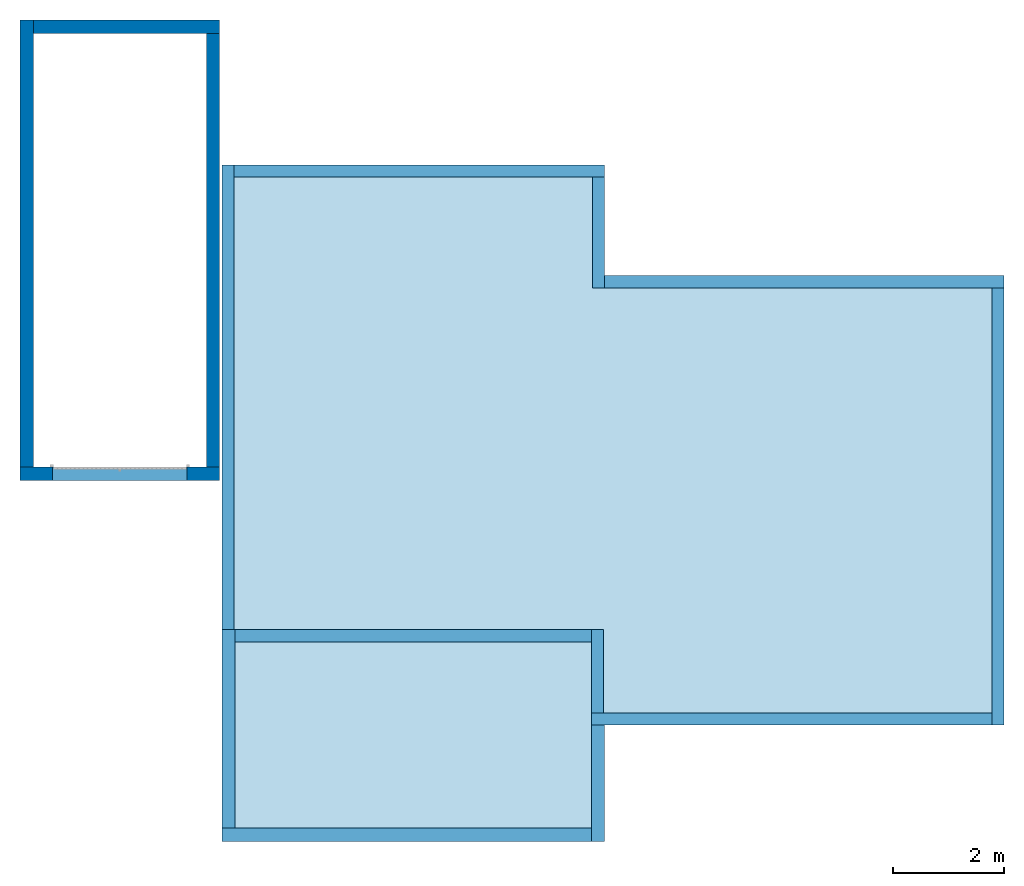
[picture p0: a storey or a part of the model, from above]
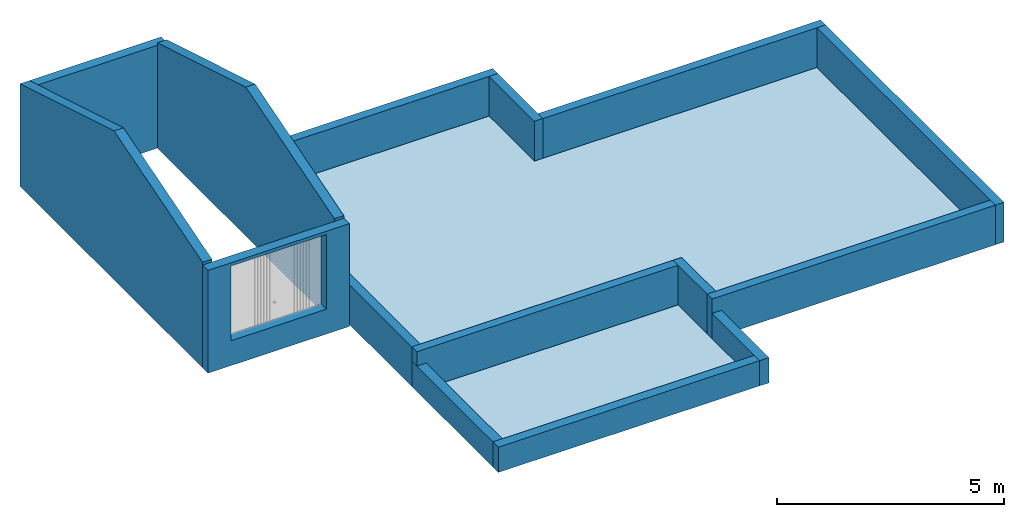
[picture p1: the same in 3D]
Properties of the parts of a building model (IFC2X3)

# File
Description: ViewDefinition [CoordinationView_V2.0]
File name: 0001
Time: 2021-03-25T11:47:55
Written by: The EXPRESS Data Manager Version 5.02.0100.07 : 28 Aug 2013
Made in: 21.0.0.383 - Exporter 21.0.0.383 - Interface utilisateur alternative 21.0.0.383
Comment: STEP Physical File produced by: The EXPRESS Data Manager Version 5.02.0100.07 : 28 Aug 2013 * Module: EDMstepFileFactory/EDMstandAlone * Creation date: Thu Mar 25 11:47:55 2021 * Host: db501 * Database: C:\Users\scosse1\AppData\Local\Temp\aa0bf1f8-5ca8-4587-8f95-3775c004460e\7c48a7ac-f314-43d9-8564-91e496e13a8a\ifc * Database version: 5507 * Database creation date: Thu Mar 25 11:47:32 2021 * Schema: IFC2X3 * Model: DataRepository.ifc * Model creation date: Thu Mar 25 11:47:32 2021 * Header model: DataRepository.ifc_HeaderModel * Header model creation date: Thu Mar 25 11:47:32 2021 * EDMuser: sdai-user * EDMgroup: sdai-group * License ID and type: 5605 : Permanent license. Expiry date: * EDMstepFileFactory options: 020000

# IfcProject, 0001
LongName: Nom du projet; Phase: Etat du projet

# IfcSite, Surface:318536
RefLatitude: 48, 52, 0, 117187; RefLongitude: 2, 19, 59, 880409; RefElevation: 0 m

# IfcBuilding
Pset_BuildingCommon - NumberOfStoreys: 6

# IfcBuildingStorey: Niveau:Ligne du Niveau (6)
Name | LongName | Elevation (m)
TN | TN | -1.07
GARAGE | GARAGE | -0.47
TERRASSE | TERRASSE | -0.17
RDC | RDC | -1.94916e-14
ARARSE GARAGE | ARARSE GARAGE | 1.7
ARASE 1 | ARASE 1 | 2.75

# IfcSpace: Cuisine 8:317210, 8
In: RDC
LongName: Cuisine; InteriorOrExteriorSpace: INTERNAL
Pset_SpaceCommon - Reference: Cuisine 8

# IfcSpace: Pièce 5:317039, 5
In: RDC
LongName: Pièce; InteriorOrExteriorSpace: INTERNAL
Pset_SpaceCommon - Reference: Pièce 5

# IfcSpace: SDB 1:317027, 1
In: RDC
LongName: SDB; InteriorOrExteriorSpace: INTERNAL
Pset_SpaceCommon - Reference: SDB 1

# IfcSpace: Salon Séjour 6:317042, 6
In: RDC
LongName: Salon Séjour; InteriorOrExteriorSpace: INTERNAL
Pset_SpaceCommon - Reference: Salon Séjour 6

# IfcSpace: WC 7:317045, 7
In: RDC
LongName: WC; InteriorOrExteriorSpace: INTERNAL
Pset_SpaceCommon - Reference: WC 7

# IfcSpace: chambre 1 4:317036, 4
In: RDC
LongName: chambre 1; InteriorOrExteriorSpace: INTERNAL
Pset_SpaceCommon - Reference: chambre 1 4

# IfcSpace: chambre 2 3:317033, 3
In: RDC
LongName: chambre 2; InteriorOrExteriorSpace: INTERNAL
Pset_SpaceCommon - Reference: chambre 2 3

# IfcSpace: chambre 3 2:317030, 2
In: RDC
LongName: chambre 3; InteriorOrExteriorSpace: INTERNAL
Pset_SpaceCommon - Reference: chambre 3 2

# IfcBuildingElementProxy: Arbre 3D - Hêtre:Hêtre - 4 m, Arbre 3D - Hêtre:Hêtre - 4 m:319941
In: RDC
Type - Pset_BuildingElementProxyCommon - Reference: Hêtre - 4 m
Type - Pset_QuantityTakeOff - Reference: Hêtre - 4 m
Pset_BuildingElementProxyCommon - sets with these values: 2

# IfcBuildingElementProxy: Plaque vitrocéramique - 4 foyers:600mm x 600mm, Plaque vitrocéramique - 4 foyers:600mm x 600mm:305606
In: 8
Type - Material: Métal - Chrome, Peinture - Grise, Verre - Plaque vitrocéramique
Type - Pset_BuildingElementProxyCommon - Reference: 600mm x 600mm
Type - Pset_QuantityTakeOff - Reference: 600mm x 600mm
Material: Métal - Chrome, Verre - Plaque vitrocéramique
Pset_BuildingElementProxyCommon - sets with these values: 2

# IfcBuildingElementProxy: RPC Arbre - Tropical:Palmier princesse - 3.6 mètres, RPC Arbre - Tropical:Palmier princesse - 3.6 mètres:323484
In: RDC
Type - Pset_BuildingElementProxyCommon - Reference: Palmier princesse - 3.6 mètres
Type - Pset_QuantityTakeOff - Reference: Palmier princesse - 3.6 mètres
Pset_BuildingElementProxyCommon - sets with these values: 2

# IfcBuildingElementProxy: RPC Femme:Lisa, RPC Femme:Lisa:324221
In: RDC
Type - Pset_BuildingElementProxyCommon - Reference: Lisa
Type - Pset_QuantityTakeOff - Reference: Lisa
Pset_BuildingElementProxyCommon - sets with these values: 2

# IfcCovering: Plafond composé:Plafond avec isolation 20 cm, Plafond composé:Plafond avec isolation 20 cm:278956
In: RDC
Type - PredefinedType: CEILING
Type - Pset_CoveringCommon - Reference: Plafond avec isolation 20 cm; TotalThickness: 0.22 m
Type - Pset_QuantityTakeOff - Reference: Plafond avec isolation 20 cm
Material: Maçonnerie - Isolant 0.2 m, Faux-plafond - Trame 600 x 600 0.02 m

# IfcDoor: Ext. Simple:Lisse - 0.90 m x 2.15 m, Ext. Simple:Lisse - 0.90 m x 2.15 m:270962
In: RDC
Type - OperationType: SINGLE_SWING_LEFT; ParameterTakesPrecedence: no; Sizeable: no; Material: PVC - Blanc (3)
Type - Ext. Simple:Lisse - 0.90 m x 2.15 m:270962 - PanelOperation: SWINGING
Type - Pset_DoorCommon - IsExternal: no; Reference: Lisse - 0.90 m x 2.15 m; ThermalTransmittance: 5.5617 kg/K/s3
Type - Pset_QuantityTakeOff - Reference: Lisse - 0.90 m x 2.15 m
OverallHeight: 2.2 m; OverallWidth: 1 m; Material: PVC - Blanc
Pset_DoorCommon - IsExternal: yes

# IfcDoor: Garage basculante:2.4m x 2m, Garage basculante:2.4m x 2m:297785
In: RDC
Type - OperationType: ROLLINGUP; ParameterTakesPrecedence: no; Sizeable: no; Material: Plastique - Noir, Peinture - Grise (2)
Type - Garage basculante:2.4m x 2m:297785 - PanelOperation: ROLLINGUP
Type - Pset_DoorCommon - IsExternal: no; Reference: 2.4m x 2m; ThermalTransmittance: 3.7021 kg/K/s3
Type - Pset_QuantityTakeOff - Reference: 2.4m x 2m
OverallHeight: 2.43 m; OverallWidth: 2.015 m; Material: Plastique - Noir, Peinture - Grise
Pset_DoorCommon - IsExternal: yes

# IfcDoor: Int. Simple:PP (0.73m x 2.04m), Int. Simple:PP (0.73m x 2.04m):277916
In: RDC
Type - ParameterTakesPrecedence: no; Sizeable: no; Material: Finition Peinture - Blanc satiné, Bois - Cadre de porte (2), Bois - Panneau de porte
Type - Pset_DoorCommon - IsExternal: no; Reference: PP (0.73m x 2.04m); ThermalTransmittance: 3.7021 kg/K/s3
Type - Pset_QuantityTakeOff - Reference: PP (0.73m x 2.04m)
OverallHeight: 2.075 m; OverallWidth: 0.8 m; Material: Finition Peinture - Blanc satiné, Bois - Panneau de porte, Bois - Cadre de porte

# IfcDoor: Int. Simple:PP (0.83m x 2.04m), Int. Simple:PP (0.83m x 2.04m):277793
In: RDC
Type - ParameterTakesPrecedence: no; Sizeable: no; Material: Bois - Cadre de porte (2), Finition Peinture - Blanc satiné, Bois - Panneau de porte
Type - Pset_DoorCommon - IsExternal: no; Reference: PP (0.83m x 2.04m); ThermalTransmittance: 3.7021 kg/K/s3
Type - Pset_QuantityTakeOff - Reference: PP (0.83m x 2.04m)
OverallHeight: 2.075 m; OverallWidth: 0.9 m; Material: Finition Peinture - Blanc satiné, Bois - Panneau de porte, Bois - Cadre de porte

# IfcDoor: Int. Simple:PP (0.83m x 2.04m) (4)
In: RDC
Type - ParameterTakesPrecedence: no; Sizeable: no; Material: Bois - Panneau de porte, Bois - Cadre de porte (2), Finition Peinture - Blanc satiné
Type - Pset_DoorCommon - IsExternal: no; Reference: PP (0.83m x 2.04m); ThermalTransmittance: 3.7021 kg/K/s3
Type - Pset_QuantityTakeOff - Reference: PP (0.83m x 2.04m)
OverallHeight: 2.075 m; OverallWidth: 0.9 m; Material: Finition Peinture - Blanc satiné, Bois - Panneau de porte, Bois - Cadre de porte
Name (Int. Simple:PP (0.83m x 2.04m):...)
277585
277677
277709
277755

# IfcDoor: Int. Simple:PP (0.83m x 2.04m), Int. Simple:PP (0.83m x 2.04m):277627
In: RDC
Type - ParameterTakesPrecedence: no; Sizeable: no; Material: Bois - Panneau de porte, Finition Peinture - Blanc satiné, Bois - Cadre de porte (2)
Type - Pset_DoorCommon - IsExternal: no; Reference: PP (0.83m x 2.04m); ThermalTransmittance: 3.7021 kg/K/s3
Type - Pset_QuantityTakeOff - Reference: PP (0.83m x 2.04m)
OverallHeight: 2.075 m; OverallWidth: 0.9 m; Material: Finition Peinture - Blanc satiné, Bois - Panneau de porte, Bois - Cadre de porte

# IfcDoor: Panneau Plein - Ouverture ext:0.73m x 2.10m, Panneau Plein - Ouverture ext:0.73m x 2.10m:272892
In: RDC
Type - OperationType: SINGLE_SWING_RIGHT; ParameterTakesPrecedence: no; Sizeable: no; Material: PVC - Blanc (3)
Type - Panneau Plein - Ouverture ext:0.73m x 2.10m:272892 - PanelOperation: SWINGING
Type - Pset_DoorCommon - IsExternal: no; Reference: 0.73m x 2.10m; ThermalTransmittance: 5.5617 kg/K/s3
Type - Pset_QuantityTakeOff - Reference: 0.73m x 2.10m
OverallHeight: 2.15 m; OverallWidth: 0.83 m; Material: PVC - Blanc

# IfcFlowTerminal: Chauffe eau:Chauffe eau, Chauffe eau:Chauffe eau:315632
In: RDC
Type - Pset_QuantityTakeOff - Reference: Chauffe eau
Pset_DistributionFlowElementCommon - Reference: Chauffe eau; sets with these values: 3

# IfcFlowTerminal: Grand évier - 2 bacs:1160mm x 500mm, Grand évier - 2 bacs:1160mm x 500mm:302428
In: 8
Type - Material: Plastique - Ton pierre, Plastique - Blanc brillant
Type - Pset_QuantityTakeOff - Reference: 1160mm x 500mm
Material: Plastique - Blanc brillant, Plastique - Ton pierre
Pset_DistributionFlowElementCommon - Reference: 1160mm x 500mm; sets with these values: 2

# IfcFlowTerminal: Lavabo moderne:Lavabo moderne, Lavabo moderne:Lavabo moderne:307324
In: 1
Type - Material: Métal - Chrome poli, Bois - Noyer naturel, Porcelaine - Blanche
Type - Pset_QuantityTakeOff - Reference: Lavabo moderne
Material: Métal - Chrome poli, Porcelaine - Blanche, Bois - Noyer naturel
Pset_DistributionFlowElementCommon - Reference: Lavabo moderne; sets with these values: 3

# IfcFlowTerminal: WC à réservoir:WC à réservoir, WC à réservoir:WC à réservoir:309013
In: 7
Type - Material: Porcelaine - Blanche, Métal - Chrome
Type - Pset_QuantityTakeOff - Reference: WC à réservoir
Pset_DistributionFlowElementCommon - Reference: WC à réservoir; sets with these values: 3

# IfcFurnishingElement: Canapé 3 places - 01:Canapé 3 places - 01, Canapé 3 places - 01:Canapé 3 places - 01:311175
In: 6
Type - Material: Métal - Chrome, Tissu - Fuschia
Type - Pset_QuantityTakeOff - Reference: Canapé 3 places - 01
Material: Tissu - Fuschia, Métal - Chrome

# IfcFurnishingElement: Lit double - 01:1346mm x 1880mm (3)
Type - Material: Bois - Bouleau, Textile - Blanc
Type - Pset_QuantityTakeOff - Reference: 1346mm x 1880mm
Name (Lit double - 01:1346mm x 1880mm:...) | In
309758 | 2
309913 | 4
309986 | 3

# IfcFurnishingElement: Table basse:900mm x 900mm x 350mm, Table basse:900mm x 900mm x 350mm:312634
In: 6
Type - Material: Métal - Alu brossé, Bois - Exotique
Type - Pset_QuantityTakeOff - Reference: 900mm x 900mm x 350mm
Material: Bois - Exotique, Métal - Alu brossé

# IfcFurnishingElement: Table et chaises:1100mm x 1100mm x 760mm, Table et chaises:1100mm x 1100mm x 760mm:314958
In: 6
Type - Material: Bois - Exotique (2), Verre - Opaque Blanc, Textile - Beige
Type - Pset_QuantityTakeOff - Reference: 1100mm x 1100mm x 760mm
Material: Bois - Exotique, Textile - Beige, Verre - Opaque Blanc

# IfcRoof: Toit de base:Toit - 200 mm (2)
Pset_QuantityTakeOff - Reference: Toit - 200 mm
Pset_RoofCommon - IsExternal: yes; Reference: Toit - 200 mm
Name (Toit de base:Toit - 200 mm:...) | In | ProjectedArea (m2) | TotalArea (m2)
287388 | ARASE 1 | 132.45 | 138.282
297901 | ARARSE GARAGE | 34.71 | 36.2383

# IfcSlab: Sol:Dalle en béton - 250 mm, Sol:Dalle en béton - 250 mm:298360
In: GARAGE
Type - PredefinedType: FLOOR; Material: Maçonnerie - Béton 0.25 m
Type - Pset_QuantityTakeOff - Reference: Dalle en béton - 250 mm
Type - Pset_ReinforcementBarPitchOfSlab - Reference: Dalle en béton - 250 mm
Type - Pset_SlabCommon - IsExternal: no; Reference: Dalle en béton - 250 mm
Pset_QuantityTakeOff - sets with these values: 2
Pset_SlabCommon - LoadBearing: no; PitchAngle: 0 deg

# IfcSlab: Sol:dalle béton 20 cm + 2 cm carrellage, Sol:dalle béton 20 cm + 2 cm carrellage:289247
In: TERRASSE
Type - PredefinedType: FLOOR; Material: Surface de dalle analytique 0.02 m, Maçonnerie - Béton 0.2 m
Type - Pset_QuantityTakeOff - Reference: dalle béton 20 cm + 2 cm carrellage
Type - Pset_ReinforcementBarPitchOfSlab - Reference: dalle béton 20 cm + 2 cm carrellage
Type - Pset_SlabCommon - IsExternal: no; Reference: dalle béton 20 cm + 2 cm carrellage
Pset_QuantityTakeOff - sets with these values: 2
Pset_SlabCommon - LoadBearing: no; PitchAngle: 0 deg

# IfcSlab: Sol:dalle béton 20 cm + 7 cm carrellage, Sol:dalle béton 20 cm + 7 cm carrellage:273148
In: RDC
Type - PredefinedType: FLOOR; Material: carrelage 0.07 m, Maçonnerie - Béton 0.2 m
Type - Pset_QuantityTakeOff - Reference: dalle béton 20 cm + 7 cm carrellage
Type - Pset_ReinforcementBarPitchOfSlab - Reference: dalle béton 20 cm + 7 cm carrellage
Type - Pset_SlabCommon - IsExternal: no; Reference: dalle béton 20 cm + 7 cm carrellage
Pset_QuantityTakeOff - sets with these values: 2
Pset_SlabCommon - LoadBearing: no; PitchAngle: 0 deg

# IfcSlab: Terre-plein:Terre-plein vs, Terre-plein:Terre-plein vs:324258
In: TN
Type - PredefinedType: FLOOR; Material: Herbe 0.01 m
Type - Pset_QuantityTakeOff - Reference: Terre-plein vs
Type - Pset_ReinforcementBarPitchOfSlab - Reference: Terre-plein vs
Type - Pset_SlabCommon - IsExternal: no; Reference: Terre-plein vs
Pset_QuantityTakeOff - sets with these values: 2
Pset_SlabCommon - PitchAngle: 0 deg

# IfcSlab: Toit de base:Toit - 200 mm (5)
Type - PredefinedType: ROOF
Type - Pset_QuantityTakeOff - Reference: Toit - 200 mm
Type - Pset_ReinforcementBarPitchOfSlab - Reference: Toit - 200 mm
Type - Pset_SlabCommon - IsExternal: yes; Reference: Toit - 200 mm
Material: Toit par défaut; Toit par défaut 0.2 m
Pset_QuantityTakeOff - sets with these values: 2
Pset_SlabCommon - PitchAngle: 16.6992 deg
Name (Toit de base:Toit - 200 mm:...) | In
3 x 287388 | ARASE 1
2 x 297901 | ARARSE GARAGE

# IfcWall: Mur de base:Int. Plâtre 70 mm, Mur de base:Int. Plâtre 70 mm:274840
In: RDC
Type - PredefinedType: STANDARD; Material: Mur par défaut 0.07 m
Type - Pset_QuantityTakeOff - Reference: Int. Plâtre 70 mm
Type - Pset_ReinforcementBarPitchOfWall - Reference: Int. Plâtre 70 mm
Type - Pset_WallCommon - IsExternal: no; Reference: Int. Plâtre 70 mm
Pset_QuantityTakeOff - sets with these values: 2
Pset_WallCommon - LoadBearing: no; ExtendToStructure: no

# IfcWallStandardCase: Mur de base:Ext. Parpaing 20 + Isolant 10 (8)
In: RDC
Type - PredefinedType: STANDARD; Material: Maçonnerie - Enduit 0.02 m, Blocs béton manufacturés 0.2 m, Maçonnerie - Isolant 0.1 m
Type - Pset_QuantityTakeOff - Reference: Ext. Parpaing 20 + Isolant 10
Type - Pset_ReinforcementBarPitchOfWall - Reference: Ext. Parpaing 20 + Isolant 10
Type - Pset_WallCommon - Reference: Ext. Parpaing 20 + Isolant 10; ThermalTransmittance: 6.5 kg/K/s3; IsExternal: no
Pset_QuantityTakeOff - sets with these values: 2
Pset_WallCommon - IsExternal: yes; ExtendToStructure: yes; LoadBearing: no
Name (Mur de base:Ext. Parpaing 20 + Isolant 10:...)
244761
244782
244849
244895
244950
244986
245107
245187

# IfcWallStandardCase: Mur de base:Int. Plâtre 70 mm (10)
In: RDC
Type - PredefinedType: STANDARD; Material: Mur par défaut 0.07 m
Type - Pset_QuantityTakeOff - Reference: Int. Plâtre 70 mm
Type - Pset_ReinforcementBarPitchOfWall - Reference: Int. Plâtre 70 mm
Type - Pset_WallCommon - IsExternal: no; Reference: Int. Plâtre 70 mm
Pset_QuantityTakeOff - sets with these values: 2
Pset_WallCommon - LoadBearing: no; ExtendToStructure: no
Name (Mur de base:Int. Plâtre 70 mm:...)
274764
275567
275614
275788
276101
276391
276780
277050
277229
277277

# IfcWallStandardCase: Mur de base:parpaing 20 + enduit 1 face 2 cm (8)
In: TN
Type - PredefinedType: STANDARD; Material: Maçonnerie - Enduit 0.02 m, Maçonnerie - Béton 0.2 m
Type - Pset_QuantityTakeOff - Reference: parpaing 20 + enduit 1 face 2 cm
Type - Pset_ReinforcementBarPitchOfWall - Reference: parpaing 20 + enduit 1 face 2 cm
Type - Pset_WallCommon - IsExternal: no; Reference: parpaing 20 + enduit 1 face 2 cm
Pset_QuantityTakeOff - sets with these values: 2
Pset_WallCommon - IsExternal: yes; LoadBearing: no; ExtendToStructure: no
Name (Mur de base:parpaing 20 + enduit 1 face 2 cm:...)
291139
291246
291309
291393
291573
291633
291901
292034

# IfcWallStandardCase: Mur de base:parpaing 20 + enduit 2 faces 2 cm (8)
Type - PredefinedType: STANDARD; Material: Maçonnerie - Enduit 0.02 m, Blocs béton manufacturés 0.2 m, Maçonnerie - Enduit 0.02 m
Type - Pset_QuantityTakeOff - Reference: parpaing 20 + enduit 2 faces 2 cm
Type - Pset_ReinforcementBarPitchOfWall - Reference: parpaing 20 + enduit 2 faces 2 cm
Type - Pset_WallCommon - IsExternal: no; Reference: parpaing 20 + enduit 2 faces 2 cm; ThermalTransmittance: 6.5 kg/K/s3
Pset_QuantityTakeOff - sets with these values: 2
Pset_WallCommon - IsExternal: yes; LoadBearing: no
Name (Mur de base:parpaing 20 + enduit 2 faces 2 cm:...) | In | ExtendToStructure
245830 | RDC | yes
289069 | TN | no
289150 | TN | no
289202 | TN | no
294534 | TN | no
294602 | TN | yes
294673 | TN | no
298190 | TN | yes

# IfcWindow: 1 Vantail - Droit:0.40m x 0.75m - Appui Alu, 1 Vantail - Droit:0.40m x 0.75m - Appui Alu:251396
In: RDC
Type - OperationType: SINGLE_PANEL; ParameterTakesPrecedence: no; Sizeable: no; Material: Fenêtre - Vitrage, Fenêtre - Poignée, Fenêtre - Cadre (2), Fenêtre - Appui
Type - Pset_QuantityTakeOff - Reference: 0.40m x 0.75m - Appui Alu
Type - Pset_WindowCommon - IsExternal: no; Reference: 0.40m x 0.75m - Appui Alu
OverallHeight: 1.08 m; OverallWidth: 0.5 m; Material: Fenêtre - Poignée, Fenêtre - Appui, Fenêtre - Vitrage, Fenêtre - Cadre
Pset_WindowCommon - IsExternal: yes

# IfcWindow: 1 Vantail - Droit:0.60 m x 0.95 m - Appui en aluminium, 1 Vantail - Droit:0.60 m x 0.95 m - Appui en aluminium:248837
In: RDC
Type - OperationType: SINGLE_PANEL; ParameterTakesPrecedence: no; Sizeable: no; Material: Fenêtre - Poignée, Fenêtre - Cadre (2), Fenêtre - Appui, Fenêtre - Vitrage
Type - Pset_QuantityTakeOff - Reference: 0.60 m x 0.95 m - Appui en aluminium
Type - Pset_WindowCommon - IsExternal: no; Reference: 0.60 m x 0.95 m - Appui en aluminium; ThermalTransmittance: 6.7069 kg/K/s3
OverallHeight: 1.08 m; OverallWidth: 0.7 m; Material: Fenêtre - Poignée, Fenêtre - Appui, Fenêtre - Vitrage, Fenêtre - Cadre
Pset_WindowCommon - IsExternal: yes

# IfcWindow: 2 Vantaux - Droits:1m x 1.05m - Appui Alu (2)
In: RDC
Type - OperationType: DOUBLE_PANEL_VERTICAL; ParameterTakesPrecedence: no; Sizeable: no; Material: Fenêtre - Vitrage, Fenêtre - Cadre (2), Fenêtre - Poignée, Fenêtre - Appui
Type - Pset_QuantityTakeOff - Reference: 1m x 1.05m - Appui Alu
Type - Pset_WindowCommon - IsExternal: no; Reference: 1m x 1.05m - Appui Alu
OverallHeight: 1.18 m; OverallWidth: 1.1 m; Material: Fenêtre - Poignée, Fenêtre - Appui, Fenêtre - Cadre, Fenêtre - Vitrage
Pset_WindowCommon - IsExternal: yes
Name (2 Vantaux - Droits:1m x 1.05m - Appui Alu:...)
248679
248721

# IfcWindow: 2 Vantaux - Droits:1m x 1.35m - Appui Alu (3)
In: RDC
Type - OperationType: DOUBLE_PANEL_VERTICAL; ParameterTakesPrecedence: no; Sizeable: no; Material: Fenêtre - Vitrage, Fenêtre - Cadre (2), Fenêtre - Appui, Fenêtre - Poignée
Type - Pset_QuantityTakeOff - Reference: 1m x 1.35m - Appui Alu
Type - Pset_WindowCommon - IsExternal: no; Reference: 1m x 1.35m - Appui Alu
OverallHeight: 1.48 m; OverallWidth: 1.1 m; Material: Fenêtre - Poignée, Fenêtre - Appui, Fenêtre - Cadre, Fenêtre - Vitrage
Pset_WindowCommon - IsExternal: yes
Name (2 Vantaux - Droits:1m x 1.35m - Appui Alu:...)
248474
248522
248567

# IfcWindow: PF 2 Vantaux - Droits:2.10 x 2.15, PF 2 Vantaux - Droits:2.10 x 2.15:257787
In: RDC
Type - OperationType: DOUBLE_PANEL_VERTICAL; ParameterTakesPrecedence: no; Sizeable: no; Material: Fenêtre - Cadre (2), Fenêtre - Appui, Fenêtre - Poignée, Fenêtre - Vitrage
Type - Pset_QuantityTakeOff - Reference: 2.10 x 2.15
Type - Pset_WindowCommon - IsExternal: no; Reference: 2.10 x 2.15
OverallHeight: 2.265 m; OverallWidth: 2.2 m; Material: Fenêtre - Poignée, Fenêtre - Appui, Fenêtre - Cadre, Fenêtre - Vitrage
Pset_WindowCommon - IsExternal: yes
